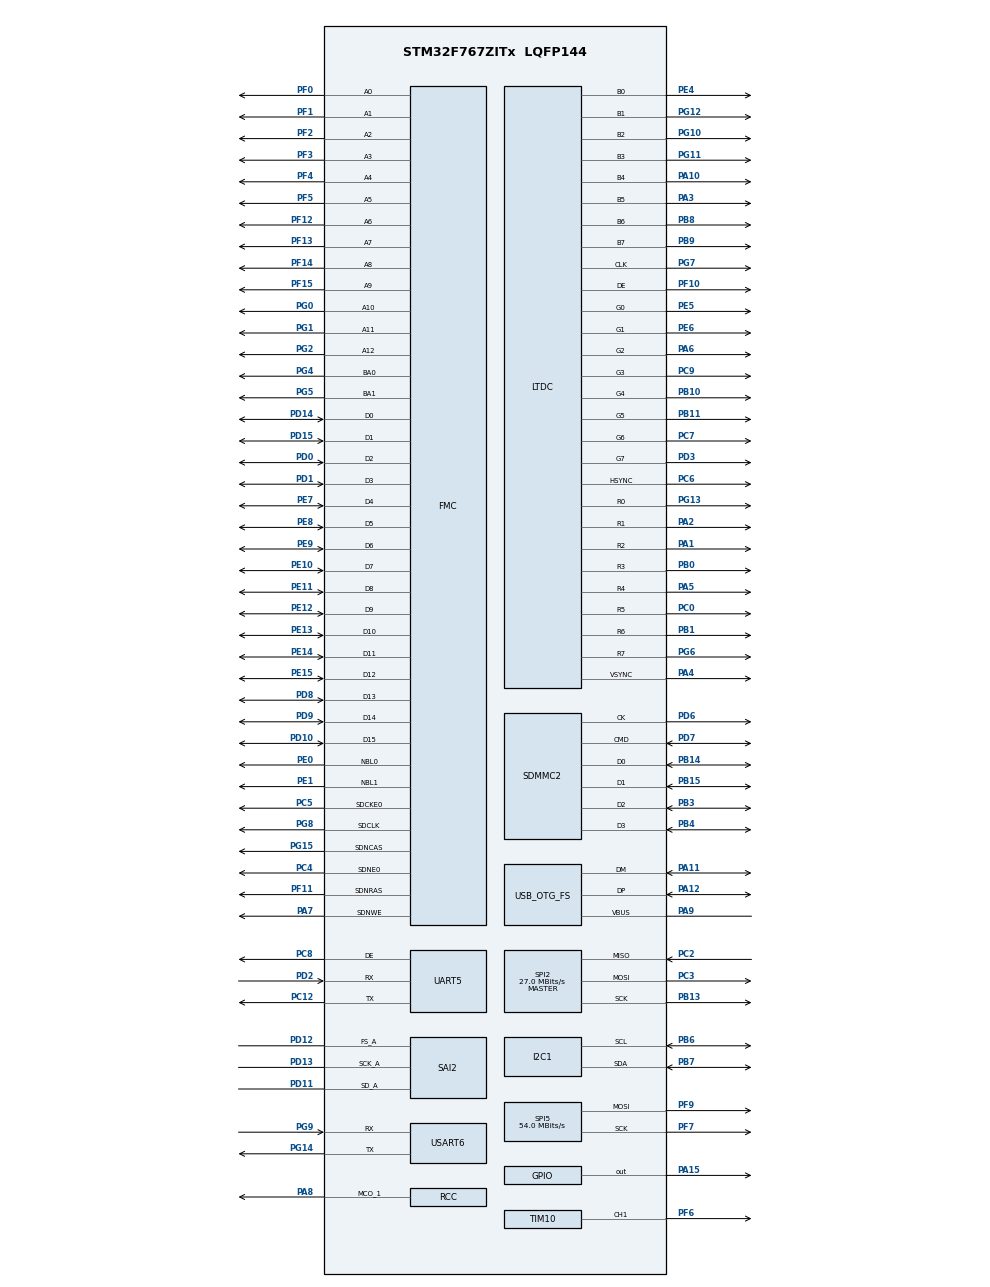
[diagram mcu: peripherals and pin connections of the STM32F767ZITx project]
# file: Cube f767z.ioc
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CORTEX_M7.ART_ACCLERATOR_ENABLE=1
CORTEX_M7.CPU_DCache=Enabled
CORTEX_M7.CPU_ICache=Enabled
CORTEX_M7.PREFETCH_ENABLE=1
Dma.I2C1_RX.2.Direction=DMA_PERIPH_TO_MEMORY
Dma.I2C1_RX.2.FIFOMode=DMA_FIFOMODE_DISABLE
Dma.I2C1_RX.2.Instance=DMA1_Stream5
Dma.I2C1_RX.2.MemDataAlignment=DMA_MDATAALIGN_BYTE
Dma.I2C1_RX.2.MemInc=DMA_MINC_ENABLE
Dma.I2C1_RX.2.Mode=DMA_NORMAL
Dma.I2C1_RX.2.PeriphDataAlignment=DMA_PDATAALIGN_BYTE
Dma.I2C1_RX.2.PeriphInc=DMA_PINC_DISABLE
Dma.I2C1_RX.2.Priority=DMA_PRIORITY_LOW
Dma.I2C1_TX.3.Direction=DMA_MEMORY_TO_PERIPH
Dma.I2C1_TX.3.FIFOMode=DMA_FIFOMODE_DISABLE
Dma.I2C1_TX.3.Instance=DMA1_Stream6
Dma.I2C1_TX.3.MemDataAlignment=DMA_MDATAALIGN_BYTE
Dma.I2C1_TX.3.MemInc=DMA_MINC_ENABLE
Dma.I2C1_TX.3.Mode=DMA_NORMAL
Dma.I2C1_TX.3.PeriphDataAlignment=DMA_PDATAALIGN_BYTE
Dma.I2C1_TX.3.PeriphInc=DMA_PINC_DISABLE
Dma.I2C1_TX.3.Priority=DMA_PRIORITY_LOW
Dma.Request0=SAI2_A
Dma.Request1=SDMMC2
Dma.Request10=SPI5_TX
Dma.Request2=I2C1_RX
Dma.Request3=I2C1_TX
Dma.Request4=SPI2_RX
Dma.Request5=SPI2_TX
Dma.Request6=USART6_RX
Dma.Request7=USART6_TX
Dma.Request8=UART5_RX
Dma.Request9=UART5_TX
Dma.SAI2_A.0.Direction=DMA_PERIPH_TO_MEMORY
Dma.SAI2_A.0.FIFOMode=DMA_FIFOMODE_DISABLE
Dma.SAI2_A.0.Instance=DMA2_Stream2
Dma.SAI2_A.0.MemDataAlignment=DMA_MDATAALIGN_WORD
Dma.SAI2_A.0.MemInc=DMA_MINC_ENABLE
Dma.SAI2_A.0.Mode=DMA_NORMAL
Dma.SAI2_A.0.PeriphDataAlignment=DMA_PDATAALIGN_WORD
Dma.SAI2_A.0.PeriphInc=DMA_PINC_DISABLE
Dma.SAI2_A.0.Priority=DMA_PRIORITY_LOW
Dma.SDMMC2.1.Direction=DMA_PERIPH_TO_MEMORY
Dma.SDMMC2.1.FIFOMode=DMA_FIFOMODE_ENABLE
Dma.SDMMC2.1.FIFOThreshold=DMA_FIFO_THRESHOLD_FULL
Dma.SDMMC2.1.Instance=DMA2_Stream0
Dma.SDMMC2.1.MemBurst=DMA_MBURST_INC4
Dma.SDMMC2.1.MemDataAlignment=DMA_MDATAALIGN_WORD
Dma.SDMMC2.1.MemInc=DMA_MINC_ENABLE
Dma.SDMMC2.1.Mode=DMA_PFCTRL
Dma.SDMMC2.1.PeriphBurst=DMA_PBURST_INC4
Dma.SDMMC2.1.PeriphDataAlignment=DMA_PDATAALIGN_WORD
Dma.SDMMC2.1.PeriphInc=DMA_PINC_DISABLE
Dma.SDMMC2.1.Priority=DMA_PRIORITY_LOW
Dma.SPI2_RX.4.Direction=DMA_PERIPH_TO_MEMORY
Dma.SPI2_RX.4.FIFOMode=DMA_FIFOMODE_DISABLE
Dma.SPI2_RX.4.Instance=DMA1_Stream1
Dma.SPI2_RX.4.MemDataAlignment=DMA_MDATAALIGN_BYTE
Dma.SPI2_RX.4.MemInc=DMA_MINC_ENABLE
Dma.SPI2_RX.4.Mode=DMA_NORMAL
Dma.SPI2_RX.4.PeriphDataAlignment=DMA_PDATAALIGN_BYTE
Dma.SPI2_RX.4.PeriphInc=DMA_PINC_DISABLE
Dma.SPI2_RX.4.Priority=DMA_PRIORITY_LOW
Dma.SPI2_TX.5.Direction=DMA_MEMORY_TO_PERIPH
Dma.SPI2_TX.5.FIFOMode=DMA_FIFOMODE_DISABLE
Dma.SPI2_TX.5.Instance=DMA1_Stream4
Dma.SPI2_TX.5.MemDataAlignment=DMA_MDATAALIGN_BYTE
Dma.SPI2_TX.5.MemInc=DMA_MINC_ENABLE
Dma.SPI2_TX.5.Mode=DMA_NORMAL
Dma.SPI2_TX.5.PeriphDataAlignment=DMA_PDATAALIGN_BYTE
Dma.SPI2_TX.5.PeriphInc=DMA_PINC_DISABLE
Dma.SPI2_TX.5.Priority=DMA_PRIORITY_LOW
Dma.SPI5_TX.10.Direction=DMA_MEMORY_TO_PERIPH
Dma.SPI5_TX.10.FIFOMode=DMA_FIFOMODE_DISABLE
Dma.SPI5_TX.10.Instance=DMA2_Stream4
Dma.SPI5_TX.10.MemDataAlignment=DMA_MDATAALIGN_BYTE
Dma.SPI5_TX.10.MemInc=DMA_MINC_ENABLE
Dma.SPI5_TX.10.Mode=DMA_NORMAL
Dma.SPI5_TX.10.PeriphDataAlignment=DMA_PDATAALIGN_BYTE
Dma.SPI5_TX.10.PeriphInc=DMA_PINC_DISABLE
Dma.SPI5_TX.10.Priority=DMA_PRIORITY_LOW
Dma.UART5_RX.8.Direction=DMA_PERIPH_TO_MEMORY
Dma.UART5_RX.8.FIFOMode=DMA_FIFOMODE_DISABLE
Dma.UART5_RX.8.Instance=DMA1_Stream0
Dma.UART5_RX.8.MemDataAlignment=DMA_MDATAALIGN_BYTE
Dma.UART5_RX.8.MemInc=DMA_MINC_ENABLE
Dma.UART5_RX.8.Mode=DMA_NORMAL
Dma.UART5_RX.8.PeriphDataAlignment=DMA_PDATAALIGN_BYTE
Dma.UART5_RX.8.PeriphInc=DMA_PINC_DISABLE
Dma.UART5_RX.8.Priority=DMA_PRIORITY_LOW
Dma.UART5_TX.9.Direction=DMA_MEMORY_TO_PERIPH
Dma.UART5_TX.9.FIFOMode=DMA_FIFOMODE_DISABLE
Dma.UART5_TX.9.Instance=DMA1_Stream7
Dma.UART5_TX.9.MemDataAlignment=DMA_MDATAALIGN_BYTE
Dma.UART5_TX.9.MemInc=DMA_MINC_ENABLE
Dma.UART5_TX.9.Mode=DMA_NORMAL
Dma.UART5_TX.9.PeriphDataAlignment=DMA_PDATAALIGN_BYTE
Dma.UART5_TX.9.PeriphInc=DMA_PINC_DISABLE
Dma.UART5_TX.9.Priority=DMA_PRIORITY_LOW
Dma.USART6_RX.6.Direction=DMA_PERIPH_TO_MEMORY
Dma.USART6_RX.6.FIFOMode=DMA_FIFOMODE_DISABLE
Dma.USART6_RX.6.Instance=DMA2_Stream1
Dma.USART6_RX.6.MemDataAlignment=DMA_MDATAALIGN_BYTE
Dma.USART6_RX.6.MemInc=DMA_MINC_ENABLE
Dma.USART6_RX.6.Mode=DMA_NORMAL
Dma.USART6_RX.6.PeriphDataAlignment=DMA_PDATAALIGN_BYTE
Dma.USART6_RX.6.PeriphInc=DMA_PINC_DISABLE
Dma.USART6_RX.6.Priority=DMA_PRIORITY_LOW
Dma.USART6_TX.7.Direction=DMA_MEMORY_TO_PERIPH
Dma.USART6_TX.7.FIFOMode=DMA_FIFOMODE_DISABLE
Dma.USART6_TX.7.Instance=DMA2_Stream6
Dma.USART6_TX.7.MemDataAlignment=DMA_MDATAALIGN_BYTE
Dma.USART6_TX.7.MemInc=DMA_MINC_ENABLE
Dma.USART6_TX.7.Mode=DMA_NORMAL
Dma.USART6_TX.7.PeriphDataAlignment=DMA_PDATAALIGN_BYTE
Dma.USART6_TX.7.PeriphInc=DMA_PINC_DISABLE
Dma.USART6_TX.7.Priority=DMA_PRIORITY_LOW
Mcu.Family=STM32F7
Mcu.Name=STM32F767ZITx
Mcu.Package=LQFP144
NVIC.DMA1_Stream0_IRQn=true\:0\:0\:false\:false\:true\:false\:true
NVIC.DMA1_Stream1_IRQn=true\:0\:0\:false\:false\:true\:false\:true
NVIC.DMA1_Stream4_IRQn=true\:0\:0\:false\:false\:true\:false\:true
NVIC.DMA1_Stream5_IRQn=true\:0\:0\:false\:false\:true\:false\:true
NVIC.DMA1_Stream6_IRQn=true\:0\:0\:false\:false\:true\:false\:true
NVIC.DMA1_Stream7_IRQn=true\:0\:0\:false\:false\:true\:false\:true
NVIC.DMA2_Stream0_IRQn=true\:0\:0\:false\:false\:true\:false\:true
NVIC.DMA2_Stream1_IRQn=true\:0\:0\:false\:false\:true\:false\:true
NVIC.DMA2_Stream2_IRQn=true\:0\:0\:false\:false\:true\:false\:true
NVIC.DMA2_Stream4_IRQn=true\:0\:0\:false\:false\:true\:false\:true
NVIC.DMA2_Stream6_IRQn=true\:0\:0\:false\:false\:true\:false\:true
NVIC.PriorityGroup=NVIC_PRIORITYGROUP_4
NVIC.TIM5_IRQn=true\:0\:0\:false\:false\:true\:false\:true
NVIC.TimeBase=TIM5_IRQn
NVIC.TimeBaseIP=TIM5
PA1.Mode=RGB888
PA1.Signal=LTDC_R2
PA10.Mode=RGB888
PA10.Signal=LTDC_B4
PA11.Mode=Device_Only
PA11.Signal=USB_OTG_FS_DM
PA12.Mode=Device_Only
PA12.Signal=USB_OTG_FS_DP
PA13.Mode=Serial_Wire
PA13.Signal=SYS_JTMS-SWDIO
PA14.Mode=Serial_Wire
PA14.Signal=SYS_JTCK-SWCLK
PA15.Signal=GPIO_Output
PA2.Mode=RGB888
PA2.Signal=LTDC_R1
PA3.Mode=RGB888
PA3.Signal=LTDC_B5
PA4.Mode=RGB888
PA4.Signal=LTDC_VSYNC
PA5.Mode=RGB888
PA5.Signal=LTDC_R4
PA6.Mode=RGB888
PA6.Signal=LTDC_G2
PA7.Signal=FMC_SDNWE
PA8.Mode=Clock-out-1
PA8.Signal=RCC_MCO_1
PA9.Mode=Activate_VBUS
PA9.Signal=USB_OTG_FS_VBUS
PB0.Mode=RGB888
PB0.Signal=LTDC_R3
PB1.Mode=RGB888
PB1.Signal=LTDC_R6
PB10.Mode=RGB888
PB10.Signal=LTDC_G4
PB11.Mode=RGB888
PB11.Signal=LTDC_G5
PB13.Mode=Full_Duplex_Master
PB13.Signal=SPI2_SCK
PB14.Mode=SD_4_bits_Wide_bus
PB14.Signal=SDMMC2_D0
PB15.Mode=SD_4_bits_Wide_bus
PB15.Signal=SDMMC2_D1
PB3.Mode=SD_4_bits_Wide_bus
PB3.Signal=SDMMC2_D2
PB4.Mode=SD_4_bits_Wide_bus
PB4.Signal=SDMMC2_D3
PB5.Signal=SPI1_MOSI
PB6.Mode=I2C
PB6.Signal=I2C1_SCL
PB7.Mode=I2C
PB7.Signal=I2C1_SDA
PB8.Mode=RGB888
PB8.Signal=LTDC_B6
PB9.Mode=RGB888
PB9.Signal=LTDC_B7
PC0.Mode=RGB888
PC0.Signal=LTDC_R5
PC12.Mode=Asynchronous
PC12.Signal=UART5_TX
PC14/OSC32_IN.Mode=LSE-External-Oscillator
PC14/OSC32_IN.Signal=RCC_OSC32_IN
PC15/OSC32_OUT.Mode=LSE-External-Oscillator
PC15/OSC32_OUT.Signal=RCC_OSC32_OUT
PC2.Mode=Full_Duplex_Master
PC2.Signal=SPI2_MISO
PC3.Mode=Full_Duplex_Master
PC3.Signal=SPI2_MOSI
PC4.Mode=SdramChipSelect1_1
PC4.Signal=FMC_SDNE0
PC5.Mode=SdramChipSelect1_1
PC5.Signal=FMC_SDCKE0
PC6.Mode=RGB888
PC6.Signal=LTDC_HSYNC
PC7.Mode=RGB888
PC7.Signal=LTDC_G6
PC8.Mode=Hardware Flow Control (RS485)
PC8.Signal=UART5_DE
PC9.Mode=RGB888
PC9.Signal=LTDC_G3
PD0.Signal=FMC_D2_DA2
PD1.Signal=FMC_D3_DA3
PD10.Signal=FMC_D15_DA15
PD11.Mode=SAI_A_AsyncSlave
PD11.Signal=SAI2_SD_A
PD12.Mode=SAI_A_AsyncSlave
PD12.Signal=SAI2_FS_A
PD13.Mode=SAI_A_AsyncSlave
PD13.Signal=SAI2_SCK_A
PD14.Signal=FMC_D0_DA0
PD15.Signal=FMC_D1_DA1
PD2.Mode=Asynchronous
PD2.Signal=UART5_RX
PD3.Mode=RGB888
PD3.Signal=LTDC_G7
PD6.Mode=SD_4_bits_Wide_bus
PD6.Signal=SDMMC2_CK
PD7.Mode=SD_4_bits_Wide_bus
PD7.Signal=SDMMC2_CMD
PD8.Signal=FMC_D13_DA13
PD9.Signal=FMC_D14_DA14
PE0.Signal=FMC_NBL0
PE1.Signal=FMC_NBL1
PE10.Signal=FMC_D7_DA7
PE11.Signal=FMC_D8_DA8
PE12.Signal=FMC_D9_DA9
PE13.Signal=FMC_D10_DA10
PE14.Signal=FMC_D11_DA11
PE15.Signal=FMC_D12_DA12
PE4.Mode=RGB888
PE4.Signal=LTDC_B0
PE5.Mode=RGB888
PE5.Signal=LTDC_G0
PE6.Mode=RGB888
PE6.Signal=LTDC_G1
PE7.Signal=FMC_D4_DA4
PE8.Signal=FMC_D5_DA5
PE9.Signal=FMC_D6_DA6
PF0.Signal=FMC_A0
PF1.Signal=FMC_A1
PF10.Mode=RGB888
PF10.Signal=LTDC_DE
PF11.Signal=FMC_SDNRAS
PF12.Signal=FMC_A6
PF13.Signal=FMC_A7
PF14.Signal=FMC_A8
PF15.Signal=FMC_A9
PF2.Signal=FMC_A2
PF3.Signal=FMC_A3
PF4.Signal=FMC_A4
PF5.Signal=FMC_A5
PF6.Signal=S_TIM10_CH1
PF7.Mode=TX_Only_Simplex_Unidirect_Master
PF7.Signal=SPI5_SCK
PF9.Mode=TX_Only_Simplex_Unidirect_Master
PF9.Signal=SPI5_MOSI
PG0.Signal=FMC_A10
PG1.Signal=FMC_A11
PG10.Mode=RGB888
PG10.Signal=LTDC_B2
PG11.Mode=RGB888
PG11.Signal=LTDC_B3
PG12.Mode=RGB888
PG12.Signal=LTDC_B1
PG13.Mode=RGB888
PG13.Signal=LTDC_R0
PG14.Mode=Asynchronous
PG14.Signal=USART6_TX
PG15.Signal=FMC_SDNCAS
PG2.Signal=FMC_A12
PG4.Signal=FMC_A14_BA0
PG5.Signal=FMC_A15_BA1
PG6.Mode=RGB888
PG6.Signal=LTDC_R7
PG7.Mode=RGB888
PG7.Signal=LTDC_CLK
PG8.Signal=FMC_SDCLK
PG9.Mode=Asynchronous
PG9.Signal=USART6_RX
PH0/OSC_IN.Mode=HSE-External-Oscillator
PH0/OSC_IN.Signal=RCC_OSC_IN
PH1/OSC_OUT.Mode=HSE-External-Oscillator
PH1/OSC_OUT.Signal=RCC_OSC_OUT
ProjectManager.HeapSize=0x200
ProjectManager.StackSize=0x400
ProjectManager.TargetToolchain=TrueSTUDIO
RCC.AHBFreq_Value=216000000
RCC.APB1CLKDivider=RCC_HCLK_DIV4
RCC.APB1Freq_Value=54000000
RCC.APB1TimFreq_Value=108000000
RCC.APB2CLKDivider=RCC_HCLK_DIV2
RCC.APB2Freq_Value=108000000
RCC.APB2TimFreq_Value=216000000
RCC.CortexFreq_Value=216000000
RCC.HCLKFreq_Value=216000000
RCC.HSE_VALUE=12000000
RCC.HSI_VALUE=16000000
RCC.I2C1CLockSelection=RCC_I2C1CLKSOURCE_HSI
RCC.PLL48CLockSelection=RCC_CLK48SOURCE_PLLSAIP
RCC.PLLM=6
RCC.PLLN=216
RCC.PLLQ=8
RCC.PLLSAIN=96
RCC.PLLSAIP=RCC_PLLSAIP_DIV4
RCC.PLLSAIQ=8
RCC.RCC_MCO1Source=RCC_MCO1SOURCE_HSE
RCC.SDMMC2ClockSelection=RCC_SDMMC2CLKSOURCE_CLK48
RCC.SYSCLKFreq_VALUE=216000000
RCC.SYSCLKSource=RCC_SYSCLKSOURCE_PLLCLK
RCC.USBFreq_Value=48000000
RCC.VCOOutputFreq_Value=432000000
SAI2.Instance-SAI_A_AsyncSlave=SAI$Index_Block_A
SAI2.Synchro-SAI_A_AsyncSlave=SAI_ASYNCHRONOUS
SAI2.VirtualMode-SAI_A_AsyncSlave=VM_SLAVE
SH.FMC_A0.0=FMC_A0,13b-sda1
SH.FMC_A1.0=FMC_A1,13b-sda1
SH.FMC_A10.0=FMC_A10,13b-sda1
SH.FMC_A11.0=FMC_A11,13b-sda1
SH.FMC_A12.0=FMC_A12,13b-sda1
SH.FMC_A14_BA0.0=FMC_BA0,FourSdramBanks1
SH.FMC_A15_BA1.0=FMC_BA1,FourSdramBanks1
SH.FMC_A2.0=FMC_A2,13b-sda1
SH.FMC_A3.0=FMC_A3,13b-sda1
SH.FMC_A4.0=FMC_A4,13b-sda1
SH.FMC_A5.0=FMC_A5,13b-sda1
SH.FMC_A6.0=FMC_A6,13b-sda1
SH.FMC_A7.0=FMC_A7,13b-sda1
SH.FMC_A8.0=FMC_A8,13b-sda1
SH.FMC_A9.0=FMC_A9,13b-sda1
SH.FMC_D0_DA0.0=FMC_D0,sd-16b-d1
SH.FMC_D10_DA10.0=FMC_D10,sd-16b-d1
SH.FMC_D11_DA11.0=FMC_D11,sd-16b-d1
SH.FMC_D12_DA12.0=FMC_D12,sd-16b-d1
SH.FMC_D13_DA13.0=FMC_D13,sd-16b-d1
SH.FMC_D14_DA14.0=FMC_D14,sd-16b-d1
SH.FMC_D15_DA15.0=FMC_D15,sd-16b-d1
SH.FMC_D1_DA1.0=FMC_D1,sd-16b-d1
SH.FMC_D2_DA2.0=FMC_D2,sd-16b-d1
SH.FMC_D3_DA3.0=FMC_D3,sd-16b-d1
SH.FMC_D4_DA4.0=FMC_D4,sd-16b-d1
SH.FMC_D5_DA5.0=FMC_D5,sd-16b-d1
SH.FMC_D6_DA6.0=FMC_D6,sd-16b-d1
SH.FMC_D7_DA7.0=FMC_D7,sd-16b-d1
SH.FMC_D8_DA8.0=FMC_D8,sd-16b-d1
SH.FMC_D9_DA9.0=FMC_D9,sd-16b-d1
SH.FMC_NBL0.0=FMC_NBL0,Sd2ByteEnable1
SH.FMC_NBL1.0=FMC_NBL1,Sd2ByteEnable1
SH.FMC_SDCLK.0=FMC_SDCLK,13b-sda1
SH.FMC_SDNCAS.0=FMC_SDNCAS,13b-sda1
SH.FMC_SDNRAS.0=FMC_SDNRAS,13b-sda1
SH.FMC_SDNWE.0=FMC_SDNWE,13b-sda1
SH.S_TIM10_CH1.0=TIM10_CH1,PWM Generation1 CH1
SPI2.BaudRatePrescaler=SPI_BAUDRATEPRESCALER_2
SPI2.CalculateBaudRate=27.0 MBits/s
SPI2.Direction=SPI_DIRECTION_2LINES
SPI2.Mode=SPI_MODE_MASTER
SPI2.VirtualType=VM_MASTER
SPI5.BaudRatePrescaler=SPI_BAUDRATEPRESCALER_2
SPI5.CalculateBaudRate=54.0 MBits/s
SPI5.Direction=SPI_DIRECTION_2LINES
SPI5.Mode=SPI_MODE_MASTER
SPI5.VirtualType=VM_MASTER
TIM10.Channel=TIM_CHANNEL_1
USART6.VirtualMode-Asynchronous=VM_ASYNC
USB_OTG_FS.VirtualMode=Device_Only
VP_DMA2D_VS_DMA2D.Mode=DMA2D_Activate
VP_SYS_VS_tim5.Mode=TIM5
VP_TIM10_VS_ClockSourceINT.Mode=Enable_Timer
board=custom

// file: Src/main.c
/* USER CODE BEGIN Header */
/**
  ******************************************************************************
  * @file           : main.c
  * @brief          : Main program body
  ******************************************************************************
  ** This notice applies to any and all portions of this file
  * that are not between comment pairs USER CODE BEGIN and
  * USER CODE END. Other portions of this file, whether
  * inserted by the user or by software development tools
  * are owned by their respective copyright owners.
  *
  * COPYRIGHT(c) 2019 STMicroelectronics
  *
  * Redistribution and use in source and binary forms, with or without modification,
  * are permitted provided that the following conditions are met:
  *   1. Redistributions of source code must retain the above copyright notice,
  *      this list of conditions and the following disclaimer.
  *   2. Redistributions in binary form must reproduce the above copyright notice,
  *      this list of conditions and the following disclaimer in the documentation
  *      and/or other materials provided with the distribution.
  *   3. Neither the name of STMicroelectronics nor the names of its contributors
  *      may be used to endorse or promote products derived from this software
  *      without specific prior written permission.
  *
  * THIS SOFTWARE IS PROVIDED BY THE COPYRIGHT HOLDERS AND CONTRIBUTORS "AS IS"
  * AND ANY EXPRESS OR IMPLIED WARRANTIES, INCLUDING, BUT NOT LIMITED TO, THE
  * IMPLIED WARRANTIES OF MERCHANTABILITY AND FITNESS FOR A PARTICULAR PURPOSE ARE
  * DISCLAIMED. IN NO EVENT SHALL THE COPYRIGHT HOLDER OR CONTRIBUTORS BE LIABLE
  * FOR ANY DIRECT, INDIRECT, INCIDENTAL, SPECIAL, EXEMPLARY, OR CONSEQUENTIAL
  * DAMAGES (INCLUDING, BUT NOT LIMITED TO, PROCUREMENT OF SUBSTITUTE GOODS OR
  * SERVICES; LOSS OF USE, DATA, OR PROFITS; OR BUSINESS INTERRUPTION) HOWEVER
  * CAUSED AND ON ANY THEORY OF LIABILITY, WHETHER IN CONTRACT, STRICT LIABILITY,
  * OR TORT (INCLUDING NEGLIGENCE OR OTHERWISE) ARISING IN ANY WAY OUT OF THE USE
  * OF THIS SOFTWARE, EVEN IF ADVISED OF THE POSSIBILITY OF SUCH DAMAGE.
  *
  ******************************************************************************
  */
/* USER CODE END Header */

#include "main.h"

DMA2D_HandleTypeDef hdma2d;

I2C_HandleTypeDef hi2c1;
DMA_HandleTypeDef hdma_i2c1_rx;
DMA_HandleTypeDef hdma_i2c1_tx;

LTDC_HandleTypeDef hltdc;

SAI_HandleTypeDef hsai_BlockA2;
DMA_HandleTypeDef hdma_sai2_a;

SD_HandleTypeDef hsd2;
DMA_HandleTypeDef hdma_sdmmc2;

SPI_HandleTypeDef hspi2;
SPI_HandleTypeDef hspi5;
DMA_HandleTypeDef hdma_spi2_rx;
DMA_HandleTypeDef hdma_spi2_tx;
DMA_HandleTypeDef hdma_spi5_tx;

TIM_HandleTypeDef htim10;

UART_HandleTypeDef huart5;
UART_HandleTypeDef huart6;
DMA_HandleTypeDef hdma_uart5_rx;
DMA_HandleTypeDef hdma_uart5_tx;
DMA_HandleTypeDef hdma_usart6_rx;
DMA_HandleTypeDef hdma_usart6_tx;

PCD_HandleTypeDef hpcd_USB_OTG_FS;

SDRAM_HandleTypeDef hsdram1;

void SystemClock_Config(void);
static void MX_GPIO_Init(void);
static void MX_DMA_Init(void);
static void MX_LTDC_Init(void);
static void MX_DMA2D_Init(void);
static void MX_USB_OTG_FS_PCD_Init(void);
static void MX_SDMMC2_SD_Init(void);
static void MX_FMC_Init(void);
static void MX_SAI2_Init(void);
static void MX_I2C1_Init(void);
static void MX_SPI2_Init(void);
static void MX_USART6_UART_Init(void);
static void MX_UART5_Init(void);
static void MX_SPI5_Init(void);
static void MX_TIM10_Init(void);

int main(void)
{

  /* Enable I-Cache---------------------------------------------------------*/
  SCB_EnableICache();

  /* Enable D-Cache---------------------------------------------------------*/
  SCB_EnableDCache();

  /* MCU Configuration--------------------------------------------------------*/

  /* Reset of all peripherals, Initializes the Flash interface and the Systick. */
  HAL_Init();

  /* Configure the system clock */
  SystemClock_Config();

  /* Initialize all configured peripherals */
  MX_GPIO_Init();
  MX_DMA_Init();
  MX_LTDC_Init();
  MX_DMA2D_Init();
  MX_USB_OTG_FS_PCD_Init();
  MX_SDMMC2_SD_Init();
  MX_FMC_Init();
  MX_SAI2_Init();
  MX_I2C1_Init();
  MX_SPI2_Init();
  MX_USART6_UART_Init();
  MX_UART5_Init();
  MX_SPI5_Init();
  MX_TIM10_Init();

  /* Infinite loop */
  while (1)
  {

  }
}

void SystemClock_Config(void)
{
  RCC_OscInitTypeDef RCC_OscInitStruct = {0};
  RCC_ClkInitTypeDef RCC_ClkInitStruct = {0};
  RCC_PeriphCLKInitTypeDef PeriphClkInitStruct = {0};

  /**Configure LSE Drive Capability
  */
  HAL_PWR_EnableBkUpAccess();
  /**Configure the main internal regulator output voltage
  */
  __HAL_RCC_PWR_CLK_ENABLE();
  __HAL_PWR_VOLTAGESCALING_CONFIG(PWR_REGULATOR_VOLTAGE_SCALE3);
  /**Initializes the CPU, AHB and APB busses clocks
  */
  RCC_OscInitStruct.OscillatorType = RCC_OSCILLATORTYPE_HSI|RCC_OSCILLATORTYPE_HSE;
  RCC_OscInitStruct.HSEState = RCC_HSE_ON;
  RCC_OscInitStruct.HSIState = RCC_HSI_ON;
  RCC_OscInitStruct.HSICalibrationValue = RCC_HSICALIBRATION_DEFAULT;
  RCC_OscInitStruct.PLL.PLLState = RCC_PLL_ON;
  RCC_OscInitStruct.PLL.PLLSource = RCC_PLLSOURCE_HSE;
  RCC_OscInitStruct.PLL.PLLM = 6;
  RCC_OscInitStruct.PLL.PLLN = 160;
  RCC_OscInitStruct.PLL.PLLP = RCC_PLLP_DIV4;
  RCC_OscInitStruct.PLL.PLLQ = 8;
  if (HAL_RCC_OscConfig(&RCC_OscInitStruct) != HAL_OK)
  {
    Error_Handler();
  }
  /**Initializes the CPU, AHB and APB busses clocks
  */
  RCC_ClkInitStruct.ClockType = RCC_CLOCKTYPE_HCLK|RCC_CLOCKTYPE_SYSCLK
                              |RCC_CLOCKTYPE_PCLK1|RCC_CLOCKTYPE_PCLK2;
  RCC_ClkInitStruct.SYSCLKSource = RCC_SYSCLKSOURCE_PLLCLK;
  RCC_ClkInitStruct.AHBCLKDivider = RCC_SYSCLK_DIV1;
  RCC_ClkInitStruct.APB1CLKDivider = RCC_HCLK_DIV2;
  RCC_ClkInitStruct.APB2CLKDivider = RCC_HCLK_DIV1;

  if (HAL_RCC_ClockConfig(&RCC_ClkInitStruct, FLASH_LATENCY_2) != HAL_OK)
  {
    Error_Handler();
  }
  PeriphClkInitStruct.PeriphClockSelection = RCC_PERIPHCLK_LTDC|RCC_PERIPHCLK_USART6
                              |RCC_PERIPHCLK_UART5|RCC_PERIPHCLK_SAI2
                              |RCC_PERIPHCLK_I2C1|RCC_PERIPHCLK_SDMMC2
                              |RCC_PERIPHCLK_CLK48;
  PeriphClkInitStruct.PLLSAI.PLLSAIN = 96;
  PeriphClkInitStruct.PLLSAI.PLLSAIR = 2;
  PeriphClkInitStruct.PLLSAI.PLLSAIQ = 8;
  PeriphClkInitStruct.PLLSAI.PLLSAIP = RCC_PLLSAIP_DIV4;
  PeriphClkInitStruct.PLLSAIDivQ = 1;
  PeriphClkInitStruct.PLLSAIDivR = RCC_PLLSAIDIVR_2;
  PeriphClkInitStruct.Sai2ClockSelection = RCC_SAI2CLKSOURCE_PLLSAI;
  PeriphClkInitStruct.Uart5ClockSelection = RCC_UART5CLKSOURCE_PCLK1;
  PeriphClkInitStruct.Usart6ClockSelection = RCC_USART6CLKSOURCE_PCLK2;
  PeriphClkInitStruct.I2c1ClockSelection = RCC_I2C1CLKSOURCE_HSI;
  PeriphClkInitStruct.Clk48ClockSelection = RCC_CLK48SOURCE_PLLSAIP;
  PeriphClkInitStruct.Sdmmc2ClockSelection = RCC_SDMMC2CLKSOURCE_CLK48;
  if (HAL_RCCEx_PeriphCLKConfig(&PeriphClkInitStruct) != HAL_OK)
  {
    Error_Handler();
  }
  HAL_RCC_MCOConfig(RCC_MCO1, RCC_MCO1SOURCE_HSE, RCC_MCODIV_1);
}

static void MX_DMA2D_Init(void)
{

  hdma2d.Instance = DMA2D;
  hdma2d.Init.Mode = DMA2D_M2M;
  hdma2d.Init.ColorMode = DMA2D_OUTPUT_ARGB8888;
  hdma2d.Init.OutputOffset = 0;
  hdma2d.LayerCfg[1].InputOffset = 0;
  hdma2d.LayerCfg[1].InputColorMode = DMA2D_INPUT_ARGB8888;
  hdma2d.LayerCfg[1].AlphaMode = DMA2D_NO_MODIF_ALPHA;
  hdma2d.LayerCfg[1].InputAlpha = 0;
  hdma2d.LayerCfg[1].AlphaInverted = DMA2D_REGULAR_ALPHA;
  hdma2d.LayerCfg[1].RedBlueSwap = DMA2D_RB_REGULAR;
  if (HAL_DMA2D_Init(&hdma2d) != HAL_OK)
  {
    Error_Handler();
  }
  if (HAL_DMA2D_ConfigLayer(&hdma2d, 1) != HAL_OK)
  {
    Error_Handler();
  }

}

static void MX_I2C1_Init(void)
{

  hi2c1.Instance = I2C1;
  hi2c1.Init.Timing = 0x00303D5B;
  hi2c1.Init.OwnAddress1 = 0;
  hi2c1.Init.AddressingMode = I2C_ADDRESSINGMODE_7BIT;
  hi2c1.Init.DualAddressMode = I2C_DUALADDRESS_DISABLE;
  hi2c1.Init.OwnAddress2 = 0;
  hi2c1.Init.OwnAddress2Masks = I2C_OA2_NOMASK;
  hi2c1.Init.GeneralCallMode = I2C_GENERALCALL_DISABLE;
  hi2c1.Init.NoStretchMode = I2C_NOSTRETCH_DISABLE;
  if (HAL_I2C_Init(&hi2c1) != HAL_OK)
  {
    Error_Handler();
  }
  /**Configure Analogue filter
  */
  if (HAL_I2CEx_ConfigAnalogFilter(&hi2c1, I2C_ANALOGFILTER_ENABLE) != HAL_OK)
  {
    Error_Handler();
  }
  /**Configure Digital filter
  */
  if (HAL_I2CEx_ConfigDigitalFilter(&hi2c1, 0) != HAL_OK)
  {
    Error_Handler();
  }

}

static void MX_LTDC_Init(void)
{

  LTDC_LayerCfgTypeDef pLayerCfg = {0};
  LTDC_LayerCfgTypeDef pLayerCfg1 = {0};

  hltdc.Instance = LTDC;
  hltdc.Init.HSPolarity = LTDC_HSPOLARITY_AL;
  hltdc.Init.VSPolarity = LTDC_VSPOLARITY_AL;
  hltdc.Init.DEPolarity = LTDC_DEPOLARITY_AL;
  hltdc.Init.PCPolarity = LTDC_PCPOLARITY_IPC;
  hltdc.Init.HorizontalSync = 7;
  hltdc.Init.VerticalSync = 3;
  hltdc.Init.AccumulatedHBP = 14;
  hltdc.Init.AccumulatedVBP = 5;
  hltdc.Init.AccumulatedActiveW = 654;
  hltdc.Init.AccumulatedActiveH = 485;
  hltdc.Init.TotalWidth = 660;
  hltdc.Init.TotalHeigh = 487;
  hltdc.Init.Backcolor.Blue = 0;
  hltdc.Init.Backcolor.Green = 0;
  hltdc.Init.Backcolor.Red = 0;
  if (HAL_LTDC_Init(&hltdc) != HAL_OK)
  {
    Error_Handler();
  }
  pLayerCfg.WindowX0 = 0;
  pLayerCfg.WindowX1 = 0;
  pLayerCfg.WindowY0 = 0;
  pLayerCfg.WindowY1 = 0;
  pLayerCfg.PixelFormat = LTDC_PIXEL_FORMAT_ARGB8888;
  pLayerCfg.Alpha = 0;
  pLayerCfg.Alpha0 = 0;
  pLayerCfg.BlendingFactor1 = LTDC_BLENDING_FACTOR1_CA;
  pLayerCfg.BlendingFactor2 = LTDC_BLENDING_FACTOR2_CA;
  pLayerCfg.FBStartAdress = 0;
  pLayerCfg.ImageWidth = 0;
  pLayerCfg.ImageHeight = 0;
  pLayerCfg.Backcolor.Blue = 0;
  pLayerCfg.Backcolor.Green = 0;
  pLayerCfg.Backcolor.Red = 0;
  if (HAL_LTDC_ConfigLayer(&hltdc, &pLayerCfg, 0) != HAL_OK)
  {
    Error_Handler();
  }
  pLayerCfg1.WindowX0 = 0;
  pLayerCfg1.WindowX1 = 0;
  pLayerCfg1.WindowY0 = 0;
  pLayerCfg1.WindowY1 = 0;
  pLayerCfg1.PixelFormat = LTDC_PIXEL_FORMAT_ARGB8888;
  pLayerCfg1.Alpha = 0;
  pLayerCfg1.Alpha0 = 0;
  pLayerCfg1.BlendingFactor1 = LTDC_BLENDING_FACTOR1_CA;
  pLayerCfg1.BlendingFactor2 = LTDC_BLENDING_FACTOR2_CA;
  pLayerCfg1.FBStartAdress = 0;
  pLayerCfg1.ImageWidth = 0;
  pLayerCfg1.ImageHeight = 0;
  pLayerCfg1.Backcolor.Blue = 0;
  pLayerCfg1.Backcolor.Green = 0;
  pLayerCfg1.Backcolor.Red = 0;
  if (HAL_LTDC_ConfigLayer(&hltdc, &pLayerCfg1, 1) != HAL_OK)
  {
    Error_Handler();
  }

}

static void MX_SAI2_Init(void)
{

  hsai_BlockA2.Instance = SAI2_Block_A;
  hsai_BlockA2.Init.Protocol = SAI_FREE_PROTOCOL;
  hsai_BlockA2.Init.AudioMode = SAI_MODESLAVE_RX;
  hsai_BlockA2.Init.DataSize = SAI_DATASIZE_8;
  hsai_BlockA2.Init.FirstBit = SAI_FIRSTBIT_MSB;
  hsai_BlockA2.Init.ClockStrobing = SAI_CLOCKSTROBING_FALLINGEDGE;
  hsai_BlockA2.Init.Synchro = SAI_ASYNCHRONOUS;
  hsai_BlockA2.Init.OutputDrive = SAI_OUTPUTDRIVE_DISABLE;
  hsai_BlockA2.Init.FIFOThreshold = SAI_FIFOTHRESHOLD_EMPTY;
  hsai_BlockA2.Init.SynchroExt = SAI_SYNCEXT_DISABLE;
  hsai_BlockA2.Init.MonoStereoMode = SAI_STEREOMODE;
  hsai_BlockA2.Init.CompandingMode = SAI_NOCOMPANDING;
  hsai_BlockA2.Init.TriState = SAI_OUTPUT_NOTRELEASED;
  hsai_BlockA2.FrameInit.FrameLength = 24;
  hsai_BlockA2.FrameInit.ActiveFrameLength = 1;
  hsai_BlockA2.FrameInit.FSDefinition = SAI_FS_STARTFRAME;
  hsai_BlockA2.FrameInit.FSPolarity = SAI_FS_ACTIVE_LOW;
  hsai_BlockA2.FrameInit.FSOffset = SAI_FS_FIRSTBIT;
  hsai_BlockA2.SlotInit.FirstBitOffset = 0;
  hsai_BlockA2.SlotInit.SlotSize = SAI_SLOTSIZE_DATASIZE;
  hsai_BlockA2.SlotInit.SlotNumber = 1;
  hsai_BlockA2.SlotInit.SlotActive = 0x00000000;
  if (HAL_SAI_Init(&hsai_BlockA2) != HAL_OK)
  {
    Error_Handler();
  }

}

static void MX_SDMMC2_SD_Init(void)
{

  hsd2.Instance = SDMMC2;
  hsd2.Init.ClockEdge = SDMMC_CLOCK_EDGE_RISING;
  hsd2.Init.ClockBypass = SDMMC_CLOCK_BYPASS_DISABLE;
  hsd2.Init.ClockPowerSave = SDMMC_CLOCK_POWER_SAVE_DISABLE;
  hsd2.Init.BusWide = SDMMC_BUS_WIDE_1B;
  hsd2.Init.HardwareFlowControl = SDMMC_HARDWARE_FLOW_CONTROL_DISABLE;
  hsd2.Init.ClockDiv = 0;
  if (HAL_SD_Init(&hsd2) != HAL_OK)
  {
    Error_Handler();
  }
  if (HAL_SD_ConfigWideBusOperation(&hsd2, SDMMC_BUS_WIDE_4B) != HAL_OK)
  {
    Error_Handler();
  }

}

static void MX_SPI2_Init(void)
{

  /* SPI2 parameter configuration*/
  hspi2.Instance = SPI2;
  hspi2.Init.Mode = SPI_MODE_MASTER;
  hspi2.Init.Direction = SPI_DIRECTION_2LINES;
  hspi2.Init.DataSize = SPI_DATASIZE_4BIT;
  hspi2.Init.CLKPolarity = SPI_POLARITY_LOW;
  hspi2.Init.CLKPhase = SPI_PHASE_1EDGE;
  hspi2.Init.NSS = SPI_NSS_SOFT;
  hspi2.Init.BaudRatePrescaler = SPI_BAUDRATEPRESCALER_2;
  hspi2.Init.FirstBit = SPI_FIRSTBIT_MSB;
  hspi2.Init.TIMode = SPI_TIMODE_DISABLE;
  hspi2.Init.CRCCalculation = SPI_CRCCALCULATION_DISABLE;
  hspi2.Init.CRCPolynomial = 7;
  hspi2.Init.CRCLength = SPI_CRC_LENGTH_DATASIZE;
  hspi2.Init.NSSPMode = SPI_NSS_PULSE_ENABLE;
  if (HAL_SPI_Init(&hspi2) != HAL_OK)
  {
    Error_Handler();
  }

}

static void MX_SPI5_Init(void)
{

  /* SPI5 parameter configuration*/
  hspi5.Instance = SPI5;
  hspi5.Init.Mode = SPI_MODE_MASTER;
  hspi5.Init.Direction = SPI_DIRECTION_2LINES;
  hspi5.Init.DataSize = SPI_DATASIZE_4BIT;
  hspi5.Init.CLKPolarity = SPI_POLARITY_LOW;
  hspi5.Init.CLKPhase = SPI_PHASE_1EDGE;
  hspi5.Init.NSS = SPI_NSS_SOFT;
  hspi5.Init.BaudRatePrescaler = SPI_BAUDRATEPRESCALER_2;
  hspi5.Init.FirstBit = SPI_FIRSTBIT_MSB;
  hspi5.Init.TIMode = SPI_TIMODE_DISABLE;
  hspi5.Init.CRCCalculation = SPI_CRCCALCULATION_DISABLE;
  hspi5.Init.CRCPolynomial = 7;
  hspi5.Init.CRCLength = SPI_CRC_LENGTH_DATASIZE;
  hspi5.Init.NSSPMode = SPI_NSS_PULSE_ENABLE;
  if (HAL_SPI_Init(&hspi5) != HAL_OK)
  {
    Error_Handler();
  }

}

static void MX_TIM10_Init(void)
{

  TIM_OC_InitTypeDef sConfigOC = {0};

  htim10.Instance = TIM10;
  htim10.Init.Prescaler = 0;
  htim10.Init.CounterMode = TIM_COUNTERMODE_UP;
  htim10.Init.Period = 0;
  htim10.Init.ClockDivision = TIM_CLOCKDIVISION_DIV1;
  htim10.Init.AutoReloadPreload = TIM_AUTORELOAD_PRELOAD_DISABLE;
  if (HAL_TIM_Base_Init(&htim10) != HAL_OK)
  {
    Error_Handler();
  }
  if (HAL_TIM_PWM_Init(&htim10) != HAL_OK)
  {
    Error_Handler();
  }
  sConfigOC.OCMode = TIM_OCMODE_PWM1;
  sConfigOC.Pulse = 0;
  sConfigOC.OCPolarity = TIM_OCPOLARITY_HIGH;
  sConfigOC.OCFastMode = TIM_OCFAST_DISABLE;
  if (HAL_TIM_PWM_ConfigChannel(&htim10, &sConfigOC, TIM_CHANNEL_1) != HAL_OK)
  {
    Error_Handler();
  }
  HAL_TIM_MspPostInit(&htim10);

}

static void MX_UART5_Init(void)
{

  huart5.Instance = UART5;
  huart5.Init.BaudRate = 115200;
  huart5.Init.WordLength = UART_WORDLENGTH_8B;
  huart5.Init.StopBits = UART_STOPBITS_1;
  huart5.Init.Parity = UART_PARITY_NONE;
  huart5.Init.Mode = UART_MODE_TX_RX;
  huart5.Init.HwFlowCtl = UART_HWCONTROL_NONE;
  huart5.Init.OverSampling = UART_OVERSAMPLING_16;
  huart5.Init.OneBitSampling = UART_ONE_BIT_SAMPLE_DISABLE;
  huart5.AdvancedInit.AdvFeatureInit = UART_ADVFEATURE_NO_INIT;
  if (HAL_RS485Ex_Init(&huart5, UART_DE_POLARITY_HIGH, 0, 0) != HAL_OK)
  {
    Error_Handler();
  }

}

static void MX_USART6_UART_Init(void)
{

  huart6.Instance = USART6;
  huart6.Init.BaudRate = 115200;
  huart6.Init.WordLength = UART_WORDLENGTH_8B;
  huart6.Init.StopBits = UART_STOPBITS_1;
  huart6.Init.Parity = UART_PARITY_NONE;
  huart6.Init.Mode = UART_MODE_TX_RX;
  huart6.Init.HwFlowCtl = UART_HWCONTROL_NONE;
  huart6.Init.OverSampling = UART_OVERSAMPLING_16;
  huart6.Init.OneBitSampling = UART_ONE_BIT_SAMPLE_DISABLE;
  huart6.AdvancedInit.AdvFeatureInit = UART_ADVFEATURE_NO_INIT;
  if (HAL_UART_Init(&huart6) != HAL_OK)
  {
    Error_Handler();
  }

}

static void MX_USB_OTG_FS_PCD_Init(void)
{

  hpcd_USB_OTG_FS.Instance = USB_OTG_FS;
  hpcd_USB_OTG_FS.Init.dev_endpoints = 6;
  hpcd_USB_OTG_FS.Init.speed = PCD_SPEED_FULL;
  hpcd_USB_OTG_FS.Init.dma_enable = DISABLE;
  hpcd_USB_OTG_FS.Init.ep0_mps = DEP0CTL_MPS_64;
  hpcd_USB_OTG_FS.Init.phy_itface = PCD_PHY_EMBEDDED;
  hpcd_USB_OTG_FS.Init.Sof_enable = DISABLE;
  hpcd_USB_OTG_FS.Init.low_power_enable = DISABLE;
  hpcd_USB_OTG_FS.Init.lpm_enable = DISABLE;
  hpcd_USB_OTG_FS.Init.vbus_sensing_enable = ENABLE;
  hpcd_USB_OTG_FS.Init.use_dedicated_ep1 = DISABLE;
  if (HAL_PCD_Init(&hpcd_USB_OTG_FS) != HAL_OK)
  {
    Error_Handler();
  }

}

static void MX_DMA_Init(void)
{
  /* DMA controller clock enable */
  __HAL_RCC_DMA2_CLK_ENABLE();
  __HAL_RCC_DMA1_CLK_ENABLE();

  /* DMA interrupt init */
  /* DMA1_Stream0_IRQn interrupt configuration */
  HAL_NVIC_SetPriority(DMA1_Stream0_IRQn, 0, 0);
  HAL_NVIC_EnableIRQ(DMA1_Stream0_IRQn);
  /* DMA1_Stream1_IRQn interrupt configuration */
  HAL_NVIC_SetPriority(DMA1_Stream1_IRQn, 0, 0);
  HAL_NVIC_EnableIRQ(DMA1_Stream1_IRQn);
  /* DMA1_Stream4_IRQn interrupt configuration */
  HAL_NVIC_SetPriority(DMA1_Stream4_IRQn, 0, 0);
  HAL_NVIC_EnableIRQ(DMA1_Stream4_IRQn);
  /* DMA1_Stream5_IRQn interrupt configuration */
  HAL_NVIC_SetPriority(DMA1_Stream5_IRQn, 0, 0);
  HAL_NVIC_EnableIRQ(DMA1_Stream5_IRQn);
  /* DMA1_Stream6_IRQn interrupt configuration */
  HAL_NVIC_SetPriority(DMA1_Stream6_IRQn, 0, 0);
  HAL_NVIC_EnableIRQ(DMA1_Stream6_IRQn);
  /* DMA1_Stream7_IRQn interrupt configuration */
  HAL_NVIC_SetPriority(DMA1_Stream7_IRQn, 0, 0);
  HAL_NVIC_EnableIRQ(DMA1_Stream7_IRQn);
  /* DMA2_Stream0_IRQn interrupt configuration */
  HAL_NVIC_SetPriority(DMA2_Stream0_IRQn, 0, 0);
  HAL_NVIC_EnableIRQ(DMA2_Stream0_IRQn);
  /* DMA2_Stream1_IRQn interrupt configuration */
  HAL_NVIC_SetPriority(DMA2_Stream1_IRQn, 0, 0);
  HAL_NVIC_EnableIRQ(DMA2_Stream1_IRQn);
  /* DMA2_Stream2_IRQn interrupt configuration */
  HAL_NVIC_SetPriority(DMA2_Stream2_IRQn, 0, 0);
  HAL_NVIC_EnableIRQ(DMA2_Stream2_IRQn);
  /* DMA2_Stream4_IRQn interrupt configuration */
  HAL_NVIC_SetPriority(DMA2_Stream4_IRQn, 0, 0);
  HAL_NVIC_EnableIRQ(DMA2_Stream4_IRQn);
  /* DMA2_Stream6_IRQn interrupt configuration */
  HAL_NVIC_SetPriority(DMA2_Stream6_IRQn, 0, 0);
  HAL_NVIC_EnableIRQ(DMA2_Stream6_IRQn);

}
/* FMC initialization function */
static void MX_FMC_Init(void)
{
  FMC_SDRAM_TimingTypeDef SdramTiming;

  /** Perform the SDRAM1 memory initialization sequence
  */
  hsdram1.Instance = FMC_SDRAM_DEVICE;
  /* hsdram1.Init */
  hsdram1.Init.SDBank = FMC_SDRAM_BANK1;
  hsdram1.Init.ColumnBitsNumber = FMC_SDRAM_COLUMN_BITS_NUM_8;
  hsdram1.Init.RowBitsNumber = FMC_SDRAM_ROW_BITS_NUM_13;
  hsdram1.Init.MemoryDataWidth = FMC_SDRAM_MEM_BUS_WIDTH_16;
  hsdram1.Init.InternalBankNumber = FMC_SDRAM_INTERN_BANKS_NUM_4;
  hsdram1.Init.CASLatency = FMC_SDRAM_CAS_LATENCY_1;
  hsdram1.Init.WriteProtection = FMC_SDRAM_WRITE_PROTECTION_DISABLE;
  hsdram1.Init.SDClockPeriod = FMC_SDRAM_CLOCK_DISABLE;
  hsdram1.Init.ReadBurst = FMC_SDRAM_RBURST_DISABLE;
  hsdram1.Init.ReadPipeDelay = FMC_SDRAM_RPIPE_DELAY_0;
  /* SdramTiming */
  SdramTiming.LoadToActiveDelay = 16;
  SdramTiming.ExitSelfRefreshDelay = 16;
  SdramTiming.SelfRefreshTime = 16;
  SdramTiming.RowCycleDelay = 16;
  SdramTiming.WriteRecoveryTime = 16;
  SdramTiming.RPDelay = 16;
  SdramTiming.RCDDelay = 16;

  if (HAL_SDRAM_Init(&hsdram1, &SdramTiming) != HAL_OK)
  {
    Error_Handler( );
  }

}

static void MX_GPIO_Init(void)
{
  GPIO_InitTypeDef GPIO_InitStruct = {0};

  /* GPIO Ports Clock Enable */
  __HAL_RCC_GPIOE_CLK_ENABLE();
  __HAL_RCC_GPIOC_CLK_ENABLE();
  __HAL_RCC_GPIOF_CLK_ENABLE();
  __HAL_RCC_GPIOH_CLK_ENABLE();
  __HAL_RCC_GPIOA_CLK_ENABLE();
  __HAL_RCC_GPIOB_CLK_ENABLE();
  __HAL_RCC_GPIOG_CLK_ENABLE();
  __HAL_RCC_GPIOD_CLK_ENABLE();

  /*Configure GPIO pin Output Level */
  HAL_GPIO_WritePin(GPIOA, GPIO_PIN_15, GPIO_PIN_RESET);

  /*Configure GPIO pin : PA8 */
  GPIO_InitStruct.Pin = GPIO_PIN_8;
  GPIO_InitStruct.Mode = GPIO_MODE_AF_PP;
  GPIO_InitStruct.Pull = GPIO_NOPULL;
  GPIO_InitStruct.Speed = GPIO_SPEED_FREQ_LOW;
  GPIO_InitStruct.Alternate = GPIO_AF0_MCO;
  HAL_GPIO_Init(GPIOA, &GPIO_InitStruct);

  /*Configure GPIO pin : PA15 */
  GPIO_InitStruct.Pin = GPIO_PIN_15;
  GPIO_InitStruct.Mode = GPIO_MODE_OUTPUT_PP;
  GPIO_InitStruct.Pull = GPIO_NOPULL;
  GPIO_InitStruct.Speed = GPIO_SPEED_FREQ_LOW;
  HAL_GPIO_Init(GPIOA, &GPIO_InitStruct);

  /*Configure GPIO pin : PB5 */
  GPIO_InitStruct.Pin = GPIO_PIN_5;
  GPIO_InitStruct.Mode = GPIO_MODE_AF_PP;
  GPIO_InitStruct.Pull = GPIO_NOPULL;
  GPIO_InitStruct.Speed = GPIO_SPEED_FREQ_VERY_HIGH;
  GPIO_InitStruct.Alternate = GPIO_AF5_SPI1;
  HAL_GPIO_Init(GPIOB, &GPIO_InitStruct);

}

void HAL_TIM_PeriodElapsedCallback(TIM_HandleTypeDef *htim)
{
  if (htim->Instance == TIM5) {
    HAL_IncTick();
  }
}

void Error_Handler(void)
{
}

/************************ (C) COPYRIGHT STMicroelectronics *****END OF FILE****/
